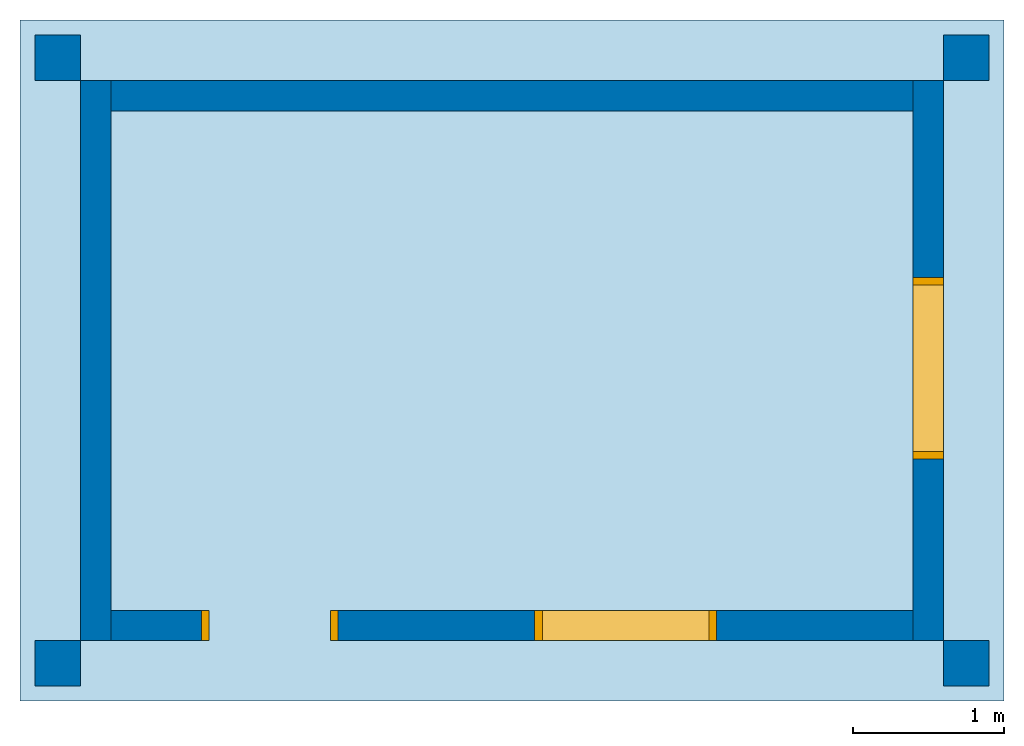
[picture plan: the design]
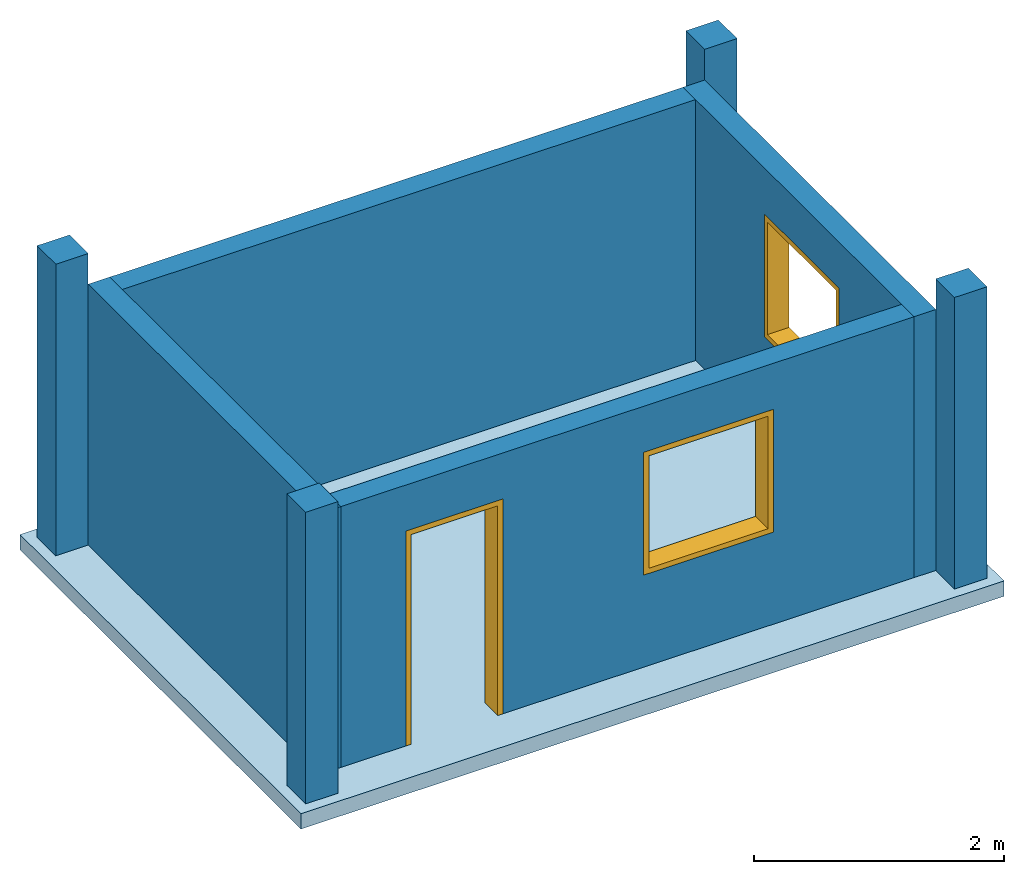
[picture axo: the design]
# One storey: 4 columns, 4 walls, 2 windows, 1 door, 1 slab, 3 openings.
"""IFC4 building model written with IfcOpenShell, lengths in metres."""

from ifc_helpers import new_model, si_unit, frame, origin_with_axes, place, context, subcontext, project, spatial, polyline, outline, extrude, boolean, material, type_object, element, fill, save


model = new_model("IFC4")

# Units and contexts
model_context = context("Model", 3, precision=1e-07, world=origin_with_axes())
body_context = subcontext(model_context, "Body", "Model", "MODEL_VIEW")
ifc_project = project(units=[si_unit("LENGTHUNIT", "METRE"), si_unit("AREAUNIT", "SQUARE_METRE"), si_unit("VOLUMEUNIT", "CUBIC_METRE")], contexts=[model_context])

# Site, building, storey
site_placement = place(None, origin_with_axes())
site = spatial("IfcSite", under=ifc_project, at=site_placement, CompositionType="ELEMENT")
building_placement = place(site_placement, origin_with_axes())
building = spatial("IfcBuilding", under=site, at=building_placement, Name="3117", CompositionType="ELEMENT")
storey_placement = place(building_placement, origin_with_axes())
storey = spatial("IfcBuildingStorey", under=building, at=storey_placement, Name="L00", CompositionType="ELEMENT", Elevation=0.0)

# Columns
ifc_material_1 = material(Name="Concrete")
column_1_placement = place(storey_placement, frame((6.0, 4.0, 0.0), z_axis=(0.0, 0.0, 1.0), x_axis=(1.0, 0.0, 0.0)))
element("IfcColumn", 1, at=column_1_placement, inside=storey, material=ifc_material_1, Name="C13", PredefinedType="COLUMN", context=body_context, shape_type="CSG", body=[
    boolean("DIFFERENCE", extrude(outline(polyline([(0.0, 0.0), (0.3, 0.0), (0.3, 0.3), (0.0, 0.3), (0.0, 0.0)])), frame((-0.15, -0.15, 0.0), z_axis=(0.0, 0.0, 1.0), x_axis=(1.0, 0.0, 0.0)), (0.0, 0.0, 1.0), 3.0), extrude(outline(polyline([(-6.25, -4.25), (0.25, -4.25), (0.25, 0.25), (-6.25, 0.25), (-6.25, -4.25)])), frame((0.0, 0.0, 2.85), z_axis=(0.0, 0.0, 1.0), x_axis=(1.0, 0.0, 0.0)), (0.0, 0.0, 1.0), 0.15)),
])
ifc_material_2 = material(Name="Concrete")
column_2_placement = place(storey_placement, origin_with_axes())
element("IfcColumn", 2, at=column_2_placement, inside=storey, material=ifc_material_2, Name="C11", PredefinedType="COLUMN", context=body_context, shape_type="CSG", body=[
    boolean("DIFFERENCE", extrude(outline(polyline([(0.0, 0.0), (0.3, 0.0), (0.3, 0.3), (0.0, 0.3), (0.0, 0.0)])), frame((-0.15, -0.15, 0.0), z_axis=(0.0, 0.0, 1.0), x_axis=(1.0, 0.0, 0.0)), (0.0, 0.0, 1.0), 3.0), extrude(outline(polyline([(-0.25, -0.25), (6.25, -0.25), (6.25, 4.25), (-0.25, 4.25), (-0.25, -0.25)])), frame((0.0, 0.0, 2.85), z_axis=(0.0, 0.0, 1.0), x_axis=(1.0, 0.0, 0.0)), (0.0, 0.0, 1.0), 0.15)),
])
ifc_material_3 = material(Name="Concrete")
column_3_placement = place(storey_placement, frame((0.0, 4.0, 0.0), z_axis=(0.0, 0.0, 1.0), x_axis=(1.0, 0.0, 0.0)))
element("IfcColumn", 3, at=column_3_placement, inside=storey, material=ifc_material_3, Name="C14", PredefinedType="COLUMN", context=body_context, shape_type="CSG", body=[
    boolean("DIFFERENCE", extrude(outline(polyline([(0.0, 0.0), (0.3, 0.0), (0.3, 0.3), (0.0, 0.3), (0.0, 0.0)])), frame((-0.15, -0.15, 0.0), z_axis=(0.0, 0.0, 1.0), x_axis=(1.0, 0.0, 0.0)), (0.0, 0.0, 1.0), 3.0), extrude(outline(polyline([(-0.25, -4.25), (6.25, -4.25), (6.25, 0.25), (-0.25, 0.25), (-0.25, -4.25)])), frame((0.0, 0.0, 2.85), z_axis=(0.0, 0.0, 1.0), x_axis=(1.0, 0.0, 0.0)), (0.0, 0.0, 1.0), 0.15)),
])
ifc_material_4 = material(Name="Concrete")
column_4_placement = place(storey_placement, frame((6.0, 0.0, 0.0), z_axis=(0.0, 0.0, 1.0), x_axis=(1.0, 0.0, 0.0)))
element("IfcColumn", 4, at=column_4_placement, inside=storey, material=ifc_material_4, Name="C12", PredefinedType="COLUMN", context=body_context, shape_type="CSG", body=[
    boolean("DIFFERENCE", extrude(outline(polyline([(0.0, 0.0), (0.3, 0.0), (0.3, 0.3), (0.0, 0.3), (0.0, 0.0)])), frame((-0.15, -0.15, 0.0), z_axis=(0.0, 0.0, 1.0), x_axis=(1.0, 0.0, 0.0)), (0.0, 0.0, 1.0), 3.0), extrude(outline(polyline([(-6.25, -0.25), (0.25, -0.25), (0.25, 4.25), (-6.25, 4.25), (-6.25, -0.25)])), frame((0.0, 0.0, 2.85), z_axis=(0.0, 0.0, 1.0), x_axis=(1.0, 0.0, 0.0)), (0.0, 0.0, 1.0), 0.15)),
])

# Slab
ifc_material_5 = material(Name="Concrete")
slab_placement = place(storey_placement, frame((0.0, 0.0, -0.15), z_axis=(0.0, 0.0, 1.0), x_axis=(1.0, 0.0, 0.0)))
element("IfcSlab", 5, at=slab_placement, inside=storey, material=ifc_material_5, Name="S00", PredefinedType="FLOOR", context=body_context, shape_type="SweptSolid", body=[
    extrude(outline(polyline([(-0.25, -0.25), (6.25, -0.25), (6.25, 4.25), (-0.25, 4.25), (-0.25, -0.25)])), origin_with_axes(), (0.0, 0.0, 1.0), 0.15),
])

# Wall, opening, window
ifc_material_6 = material(Name="Blockwork")
wall_type = type_object("IfcWallType", Name="Block 200", PredefinedType="STANDARD", material=ifc_material_6)
wall_1_placement = place(storey_placement, frame((5.85, 0.15, 0.0), z_axis=(0.0, 0.0, 1.0), x_axis=(0.0, 1.0, 0.0)))
wall_1 = element("IfcWall", 6, at=wall_1_placement, inside=storey, type_object=wall_type, Name="Wall 1-2", PredefinedType="STANDARD", context=body_context, shape_type="SweptSolid", body=[
    extrude(outline(polyline([(0.0, 0.0), (3.7, 0.0), (3.7, 0.2), (0.0, 0.2), (0.0, 0.0)])), origin_with_axes(), (0.0, 0.0, 1.0), 2.55),
])
opening_1_placement = place(wall_1_placement, frame((1.2, -1e-06, 0.9), z_axis=(0.0, 0.0, 1.0), x_axis=(1.0, 0.0, 0.0)))
opening_1 = element("IfcOpeningElement", 7, at=opening_1_placement, cuts=wall_1, PredefinedType="OPENING", context=body_context, shape_type="SweptSolid", body=[
    extrude(outline(polyline([(0.0, 0.0), (1.2, 0.0), (1.2, 0.200002), (0.0, 0.200002), (0.0, 0.0)])), origin_with_axes(), (0.0, 0.0, 1.0), 1.2),
])
window_1_placement = place(opening_1_placement, frame((0.0, 1e-06, 0.0), z_axis=(0.0, 0.0, 1.0), x_axis=(1.0, 0.0, 0.0)))
window_1 = element("IfcWindow", 8, at=window_1_placement, inside=storey, Name="WIN12", OverallHeight=1.2, OverallWidth=1.2, PartitioningType="NOTDEFINED", PredefinedType="WINDOW", context=body_context, shape_type="SweptSolid", body=[
    extrude(outline(polyline([(0.0, 0.0), (0.05, 0.0), (0.05, 0.2), (0.0, 0.2), (0.0, 0.0)])), origin_with_axes(), (0.0, 0.0, 1.0), 1.2),
    extrude(outline(polyline([(0.0, 0.0), (0.05, 0.0), (0.05, 0.2), (0.0, 0.2), (0.0, 0.0)])), frame((1.15, 0.0, 0.0), z_axis=(0.0, 0.0, 1.0), x_axis=(1.0, 0.0, 0.0)), (0.0, 0.0, 1.0), 1.2),
    extrude(outline(polyline([(0.0, 0.0), (1.1, 0.0), (1.1, 0.2), (0.0, 0.2), (0.0, 0.0)])), frame((0.05, 0.0, 0.0), z_axis=(0.0, 0.0, 1.0), x_axis=(1.0, 0.0, 0.0)), (0.0, 0.0, 1.0), 0.05),
    extrude(outline(polyline([(0.0, 0.0), (1.1, 0.0), (1.1, 0.2), (0.0, 0.2), (0.0, 0.0)])), frame((0.05, 0.0, 1.15), z_axis=(0.0, 0.0, 1.0), x_axis=(1.0, 0.0, 0.0)), (0.0, 0.0, 1.0), 0.05),
])
fill(opening_1, window_1)

# Wall, openings, door, window
wall_2_placement = place(storey_placement, frame((0.15, 0.15, 0.0), z_axis=(0.0, 0.0, 1.0), x_axis=(1.0, 0.0, 0.0)))
wall_2 = element("IfcWall", 9, at=wall_2_placement, inside=storey, type_object=wall_type, Name="Wall 1-1", PredefinedType="STANDARD", context=body_context, shape_type="SweptSolid", body=[
    extrude(outline(polyline([(0.0, 0.0), (5.7, 0.0), (5.7, 0.2), (0.0, 0.2), (0.0, 0.0)])), origin_with_axes(), (0.0, 0.0, 1.0), 2.55),
])
opening_2_placement = place(wall_2_placement, frame((0.8, -1e-06, 0.0), z_axis=(0.0, 0.0, 1.0), x_axis=(1.0, 0.0, 0.0)))
opening_2 = element("IfcOpeningElement", 10, at=opening_2_placement, cuts=wall_2, PredefinedType="OPENING", context=body_context, shape_type="SweptSolid", body=[
    extrude(outline(polyline([(0.0, 0.0), (0.9, 0.0), (0.9, 0.200002), (0.0, 0.200002), (0.0, 0.0)])), origin_with_axes(), (0.0, 0.0, 1.0), 2.1),
])
opening_3_placement = place(wall_2_placement, frame((3.0, -1e-06, 0.9), z_axis=(0.0, 0.0, 1.0), x_axis=(1.0, 0.0, 0.0)))
opening_3 = element("IfcOpeningElement", 11, at=opening_3_placement, cuts=wall_2, PredefinedType="OPENING", context=body_context, shape_type="SweptSolid", body=[
    extrude(outline(polyline([(0.0, 0.0), (1.2, 0.0), (1.2, 0.200002), (0.0, 0.200002), (0.0, 0.0)])), origin_with_axes(), (0.0, 0.0, 1.0), 1.2),
])
door_placement = place(opening_2_placement, frame((0.0, 1e-06, 0.0), z_axis=(0.0, 0.0, 1.0), x_axis=(1.0, 0.0, 0.0)))
door = element("IfcDoor", 12, at=door_placement, inside=storey, Name="D01", OperationType="NOTDEFINED", OverallHeight=2.1, OverallWidth=0.9, PredefinedType="DOOR", context=body_context, shape_type="SweptSolid", body=[
    extrude(outline(polyline([(0.0, 0.0), (0.05, 0.0), (0.05, 0.2), (0.0, 0.2), (0.0, 0.0)])), origin_with_axes(), (0.0, 0.0, 1.0), 2.05),
    extrude(outline(polyline([(0.0, 0.0), (0.05, 0.0), (0.05, 0.2), (0.0, 0.2), (0.0, 0.0)])), frame((0.85, 0.0, 0.0), z_axis=(0.0, 0.0, 1.0), x_axis=(1.0, 0.0, 0.0)), (0.0, 0.0, 1.0), 2.05),
    extrude(outline(polyline([(0.0, 0.0), (0.9, 0.0), (0.9, 0.2), (0.0, 0.2), (0.0, 0.0)])), frame((0.0, 0.0, 2.05), z_axis=(0.0, 0.0, 1.0), x_axis=(1.0, 0.0, 0.0)), (0.0, 0.0, 1.0), 0.05),
])
fill(opening_2, door)
window_2_placement = place(opening_3_placement, frame((0.0, 1e-06, 0.0), z_axis=(0.0, 0.0, 1.0), x_axis=(1.0, 0.0, 0.0)))
window_2 = element("IfcWindow", 13, at=window_2_placement, inside=storey, Name="WIN11", OverallHeight=1.2, OverallWidth=1.2, PartitioningType="NOTDEFINED", PredefinedType="WINDOW", context=body_context, shape_type="SweptSolid", body=[
    extrude(outline(polyline([(0.0, 0.0), (0.05, 0.0), (0.05, 0.2), (0.0, 0.2), (0.0, 0.0)])), origin_with_axes(), (0.0, 0.0, 1.0), 1.2),
    extrude(outline(polyline([(0.0, 0.0), (0.05, 0.0), (0.05, 0.2), (0.0, 0.2), (0.0, 0.0)])), frame((1.15, 0.0, 0.0), z_axis=(0.0, 0.0, 1.0), x_axis=(1.0, 0.0, 0.0)), (0.0, 0.0, 1.0), 1.2),
    extrude(outline(polyline([(0.0, 0.0), (1.1, 0.0), (1.1, 0.2), (0.0, 0.2), (0.0, 0.0)])), frame((0.05, 0.0, 0.0), z_axis=(0.0, 0.0, 1.0), x_axis=(1.0, 0.0, 0.0)), (0.0, 0.0, 1.0), 0.05),
    extrude(outline(polyline([(0.0, 0.0), (1.1, 0.0), (1.1, 0.2), (0.0, 0.2), (0.0, 0.0)])), frame((0.05, 0.0, 1.15), z_axis=(0.0, 0.0, 1.0), x_axis=(1.0, 0.0, 0.0)), (0.0, 0.0, 1.0), 0.05),
])
fill(opening_3, window_2)

# Walls
wall_3_placement = place(storey_placement, frame((0.15, 3.85, 0.0), z_axis=(0.0, 0.0, 1.0), x_axis=(0.0, -1.0, 0.0)))
element("IfcWall", 14, at=wall_3_placement, inside=storey, type_object=wall_type, Name="Wall 1-4", PredefinedType="STANDARD", context=body_context, shape_type="SweptSolid", body=[
    extrude(outline(polyline([(0.0, 0.0), (3.7, 0.0), (3.7, 0.2), (0.0, 0.2), (0.0, 0.0)])), origin_with_axes(), (0.0, 0.0, 1.0), 2.55),
])
wall_4_placement = place(storey_placement, frame((5.85, 3.85, 0.0), z_axis=(0.0, 0.0, 1.0), x_axis=(-1.0, 0.0, 0.0)))
element("IfcWall", 15, at=wall_4_placement, inside=storey, type_object=wall_type, Name="Wall 1-3", PredefinedType="STANDARD", context=body_context, shape_type="SweptSolid", body=[
    extrude(outline(polyline([(0.0, 0.0), (5.7, 0.0), (5.7, 0.2), (0.0, 0.2), (0.0, 0.0)])), origin_with_axes(), (0.0, 0.0, 1.0), 2.55),
])

save(model, "model.ifc")
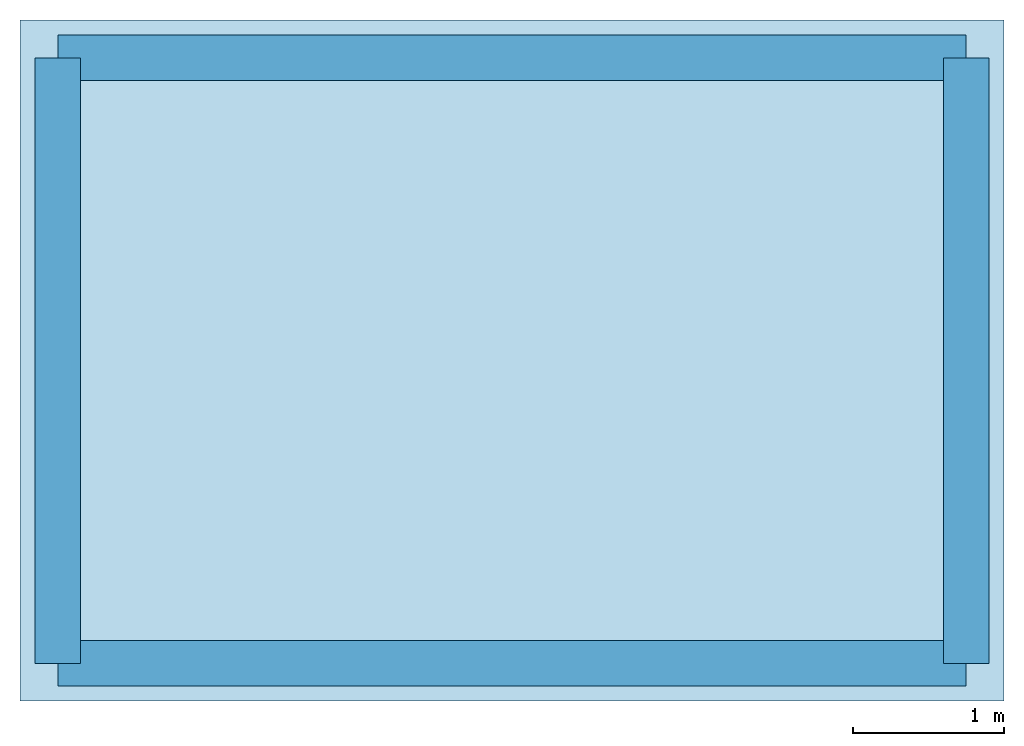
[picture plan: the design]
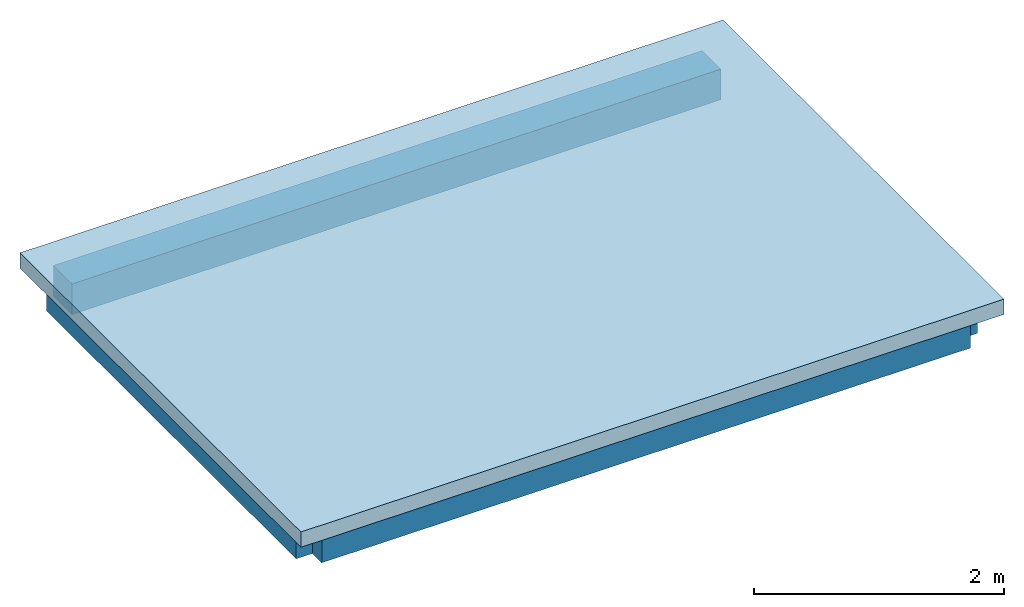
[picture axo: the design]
# One storey: 4 beams, 1 slab.
"""IFC4 building model written with IfcOpenShell, lengths in metres."""

from ifc_helpers import new_model, si_unit, frame, origin_with_axes, place, context, subcontext, project, spatial, polyline, outline, extrude, boolean, material, element, save


model = new_model("IFC4")

# Units and contexts
model_context = context("Model", 3, precision=1e-07, world=origin_with_axes())
body_context = subcontext(model_context, "Body", "Model", "MODEL_VIEW")
ifc_project = project(units=[si_unit("LENGTHUNIT", "METRE"), si_unit("AREAUNIT", "SQUARE_METRE"), si_unit("VOLUMEUNIT", "CUBIC_METRE")], contexts=[model_context])

# Site, building, storey
site_placement = place(None, origin_with_axes())
site = spatial("IfcSite", under=ifc_project, at=site_placement, CompositionType="ELEMENT")
building_placement = place(site_placement, origin_with_axes())
building = spatial("IfcBuilding", under=site, at=building_placement, Name="3117", CompositionType="ELEMENT")
storey_placement = place(building_placement, frame((0.0, 0.0, 6.0), z_axis=(0.0, 0.0, 1.0), x_axis=(1.0, 0.0, 0.0)))
storey = spatial("IfcBuildingStorey", under=building, at=storey_placement, Name="L02", CompositionType="ELEMENT", Elevation=6.0)

# Beams
ifc_material_1 = material(Name="Concrete")
beam_1_placement = place(storey_placement, frame((0.0, 0.0, -0.45), z_axis=(0.0, 0.0, 1.0), x_axis=(1.0, 0.0, 0.0)))
element("IfcBeam", 1, at=beam_1_placement, inside=storey, material=ifc_material_1, Name="B21", PredefinedType="BEAM", context=body_context, shape_type="CSG", body=[
    boolean("DIFFERENCE", extrude(outline(polyline([(0.0, 0.0), (6.0, 0.0), (6.0, 0.3), (0.0, 0.3), (0.0, 0.0)])), frame((0.0, -0.15, 0.0), z_axis=(0.0, 0.0, 1.0), x_axis=(1.0, 0.0, 0.0)), (0.0, 0.0, 1.0), 0.45), extrude(outline(polyline([(-0.25, -0.25), (6.25, -0.25), (6.25, 4.25), (-0.25, 4.25), (-0.25, -0.25)])), frame((0.0, 0.0, 0.3), z_axis=(0.0, 0.0, 1.0), x_axis=(1.0, 0.0, 0.0)), (0.0, 0.0, 1.0), 0.15)),
])
ifc_material_2 = material(Name="Concrete")
beam_2_placement = place(storey_placement, frame((0.0, 4.0, -0.45), z_axis=(0.0, 0.0, 1.0), x_axis=(0.0, -1.0, 0.0)))
element("IfcBeam", 2, at=beam_2_placement, inside=storey, material=ifc_material_2, Name="B24", PredefinedType="BEAM", context=body_context, shape_type="CSG", body=[
    boolean("DIFFERENCE", extrude(outline(polyline([(0.0, 0.0), (4.0, 0.0), (4.0, 0.3), (0.0, 0.3), (0.0, 0.0)])), frame((0.0, -0.15, 0.0), z_axis=(0.0, 0.0, 1.0), x_axis=(1.0, 0.0, 0.0)), (0.0, 0.0, 1.0), 0.45), extrude(outline(polyline([(4.25, -0.25), (4.25, 6.25), (-0.25, 6.25), (-0.25, -0.25), (4.25, -0.25)])), frame((0.0, 0.0, 0.3), z_axis=(0.0, 0.0, 1.0), x_axis=(1.0, 0.0, 0.0)), (0.0, 0.0, 1.0), 0.15)),
])
ifc_material_3 = material(Name="Concrete")
beam_3_placement = place(storey_placement, frame((6.0, 4.0, -0.45), z_axis=(0.0, 0.0, 1.0), x_axis=(-1.0, 0.0, 0.0)))
element("IfcBeam", 3, at=beam_3_placement, inside=storey, material=ifc_material_3, Name="B23", PredefinedType="BEAM", context=body_context, shape_type="CSG", body=[
    boolean("DIFFERENCE", extrude(outline(polyline([(0.0, 0.0), (6.0, 0.0), (6.0, 0.3), (0.0, 0.3), (0.0, 0.0)])), frame((0.0, -0.15, 0.0), z_axis=(0.0, 0.0, 1.0), x_axis=(1.0, 0.0, 0.0)), (0.0, 0.0, 1.0), 0.45), extrude(outline(polyline([(6.25, 4.25), (-0.25, 4.25), (-0.25, -0.25), (6.25, -0.25), (6.25, 4.25)])), frame((0.0, 0.0, 0.3), z_axis=(0.0, 0.0, 1.0), x_axis=(1.0, 0.0, 0.0)), (0.0, 0.0, 1.0), 0.15)),
])
ifc_material_4 = material(Name="Concrete")
beam_4_placement = place(storey_placement, frame((6.0, 0.0, -0.45), z_axis=(0.0, 0.0, 1.0), x_axis=(0.0, 1.0, 0.0)))
element("IfcBeam", 4, at=beam_4_placement, inside=storey, material=ifc_material_4, Name="B22", PredefinedType="BEAM", context=body_context, shape_type="CSG", body=[
    boolean("DIFFERENCE", extrude(outline(polyline([(0.0, 0.0), (4.0, 0.0), (4.0, 0.3), (0.0, 0.3), (0.0, 0.0)])), frame((0.0, -0.15, 0.0), z_axis=(0.0, 0.0, 1.0), x_axis=(1.0, 0.0, 0.0)), (0.0, 0.0, 1.0), 0.45), extrude(outline(polyline([(-0.25, 6.25), (-0.25, -0.25), (4.25, -0.25), (4.25, 6.25), (-0.25, 6.25)])), frame((0.0, 0.0, 0.3), z_axis=(0.0, 0.0, 1.0), x_axis=(1.0, 0.0, 0.0)), (0.0, 0.0, 1.0), 0.15)),
])

# Slab
ifc_material_5 = material(Name="Concrete")
slab_placement = place(storey_placement, frame((0.0, 0.0, -0.15), z_axis=(0.0, 0.0, 1.0), x_axis=(1.0, 0.0, 0.0)))
element("IfcSlab", 5, at=slab_placement, inside=storey, material=ifc_material_5, Name="S02", PredefinedType="FLOOR", context=body_context, shape_type="SweptSolid", body=[
    extrude(outline(polyline([(-0.25, -0.25), (6.25, -0.25), (6.25, 4.25), (-0.25, 4.25), (-0.25, -0.25)])), origin_with_axes(), (0.0, 0.0, 1.0), 0.15),
])

save(model, "model.ifc")
